VERSION 5.8 ;
BUSBITCHARS "[]" ;
DIVIDERCHAR "/" ;

# R1 pad ring reference abstract (empty core). Units um. Pins: bondpad TopMetal2 squares (70 x 70 um).
# Core window and ring: see README. Obstructions: core power ring (TopMetal1 / TopMetal2).

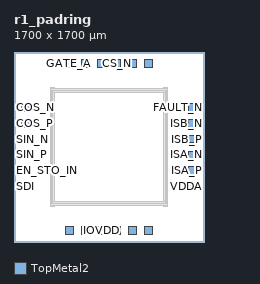
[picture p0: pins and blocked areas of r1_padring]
MACRO r1_padring
  CLASS BLOCK ;
  ORIGIN 0 0 ;
  FOREIGN r1_padring 0 0 ;
  SIZE 1700 BY 1700 ;
  SYMMETRY X Y ;
  PIN VDD
    DIRECTION INOUT ;
    USE POWER ;
    PORT
      LAYER TopMetal2 ;
        RECT 460.000 66.000 530.000 136.000 ;
    END
  END VDD
  PIN VSS
    DIRECTION INOUT ;
    USE GROUND ;
    PORT
      LAYER TopMetal2 ;
        RECT 602.000 66.000 672.000 136.000 ;
        RECT 1028.000 66.000 1098.000 136.000 ;
    END
  END VSS
  PIN IOVDD
    DIRECTION INOUT ;
    USE POWER ;
    PORT
      LAYER TopMetal2 ;
        RECT 744.000 66.000 814.000 136.000 ;
    END
  END IOVDD
  PIN IOVSS
    DIRECTION INOUT ;
    USE GROUND ;
    PORT
      LAYER TopMetal2 ;
        RECT 886.000 66.000 956.000 136.000 ;
        RECT 1170.000 66.000 1240.000 136.000 ;
    END
  END IOVSS
  PIN VDDA
    DIRECTION INOUT ;
    USE POWER ;
    PORT
      LAYER TopMetal2 ;
        RECT 1564.000 460.000 1634.000 530.000 ;
    END
  END VDDA
  PIN ISA_P
    DIRECTION INOUT ;
    USE SIGNAL ;
    PORT
      LAYER TopMetal2 ;
        RECT 1564.000 602.000 1634.000 672.000 ;
    END
  END ISA_P
  PIN ISA_N
    DIRECTION INOUT ;
    USE SIGNAL ;
    PORT
      LAYER TopMetal2 ;
        RECT 1564.000 744.000 1634.000 814.000 ;
    END
  END ISA_N
  PIN ISB_P
    DIRECTION INOUT ;
    USE SIGNAL ;
    PORT
      LAYER TopMetal2 ;
        RECT 1564.000 886.000 1634.000 956.000 ;
    END
  END ISB_P
  PIN ISB_N
    DIRECTION INOUT ;
    USE SIGNAL ;
    PORT
      LAYER TopMetal2 ;
        RECT 1564.000 1028.000 1634.000 1098.000 ;
    END
  END ISB_N
  PIN FAULT_N
    DIRECTION INOUT ;
    USE SIGNAL ;
    PORT
      LAYER TopMetal2 ;
        RECT 1564.000 1170.000 1634.000 1240.000 ;
    END
  END FAULT_N
  PIN GATE_A
    DIRECTION INOUT ;
    USE SIGNAL ;
    PORT
      LAYER TopMetal2 ;
        RECT 460.000 1564.000 530.000 1634.000 ;
    END
  END GATE_A
  PIN GATE_B
    DIRECTION INOUT ;
    USE SIGNAL ;
    PORT
      LAYER TopMetal2 ;
        RECT 602.000 1564.000 672.000 1634.000 ;
    END
  END GATE_B
  PIN GATE_C
    DIRECTION INOUT ;
    USE SIGNAL ;
    PORT
      LAYER TopMetal2 ;
        RECT 744.000 1564.000 814.000 1634.000 ;
    END
  END GATE_C
  PIN CS_N
    DIRECTION INOUT ;
    USE SIGNAL ;
    PORT
      LAYER TopMetal2 ;
        RECT 886.000 1564.000 956.000 1634.000 ;
    END
  END CS_N
  PIN MA_SCLK
    DIRECTION INOUT ;
    USE SIGNAL ;
    PORT
      LAYER TopMetal2 ;
        RECT 1028.000 1564.000 1098.000 1634.000 ;
    END
  END MA_SCLK
  PIN SLO_SDO
    DIRECTION INOUT ;
    USE SIGNAL ;
    PORT
      LAYER TopMetal2 ;
        RECT 1170.000 1564.000 1240.000 1634.000 ;
    END
  END SLO_SDO
  PIN SDI
    DIRECTION INOUT ;
    USE SIGNAL ;
    PORT
      LAYER TopMetal2 ;
        RECT 66.000 460.000 136.000 530.000 ;
    END
  END SDI
  PIN EN_STO_IN
    DIRECTION INOUT ;
    USE SIGNAL ;
    PORT
      LAYER TopMetal2 ;
        RECT 66.000 602.000 136.000 672.000 ;
    END
  END EN_STO_IN
  PIN SIN_P
    DIRECTION INOUT ;
    USE SIGNAL ;
    PORT
      LAYER TopMetal2 ;
        RECT 66.000 744.000 136.000 814.000 ;
    END
  END SIN_P
  PIN SIN_N
    DIRECTION INOUT ;
    USE SIGNAL ;
    PORT
      LAYER TopMetal2 ;
        RECT 66.000 886.000 136.000 956.000 ;
    END
  END SIN_N
  PIN COS_P
    DIRECTION INOUT ;
    USE SIGNAL ;
    PORT
      LAYER TopMetal2 ;
        RECT 66.000 1028.000 136.000 1098.000 ;
    END
  END COS_P
  PIN COS_N
    DIRECTION INOUT ;
    USE SIGNAL ;
    PORT
      LAYER TopMetal2 ;
        RECT 66.000 1170.000 136.000 1240.000 ;
    END
  END COS_N
  OBS
    LAYER TopMetal1 ;
      RECT 324.820 321.000 339.820 1379.000 ;
      RECT 344.820 321.000 361.800 1379.000 ;
      RECT 1340.420 321.000 1355.420 1379.000 ;
      RECT 1360.420 321.000 1375.420 1379.000 ;
      RECT 1340.420 347.160 1355.420 1352.300 ;
      RECT 344.820 347.160 359.820 1352.300 ;
      RECT 1360.420 327.160 1375.420 1372.300 ;
      RECT 324.820 327.160 339.820 1372.300 ;
    LAYER TopMetal2 ;
      RECT 344.820 1337.300 1355.420 1352.300 ;
      RECT 344.820 347.160 1355.420 362.160 ;
      RECT 328.000 1357.300 1372.000 1372.300 ;
      RECT 328.000 327.160 1372.000 342.160 ;
  END
END r1_padring

END LIBRARY
